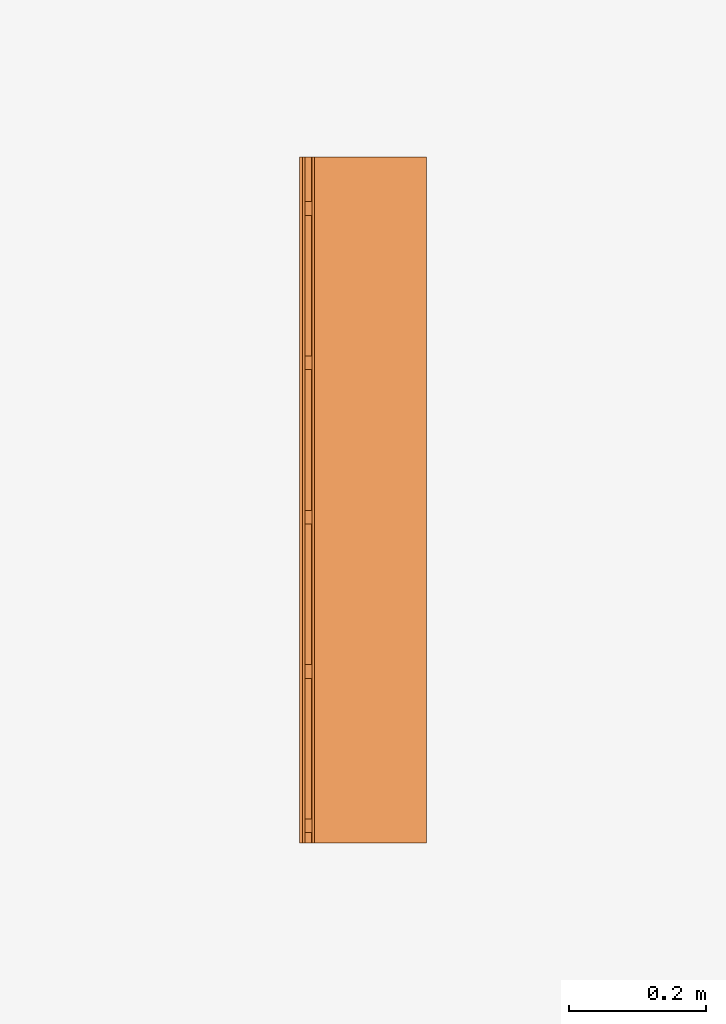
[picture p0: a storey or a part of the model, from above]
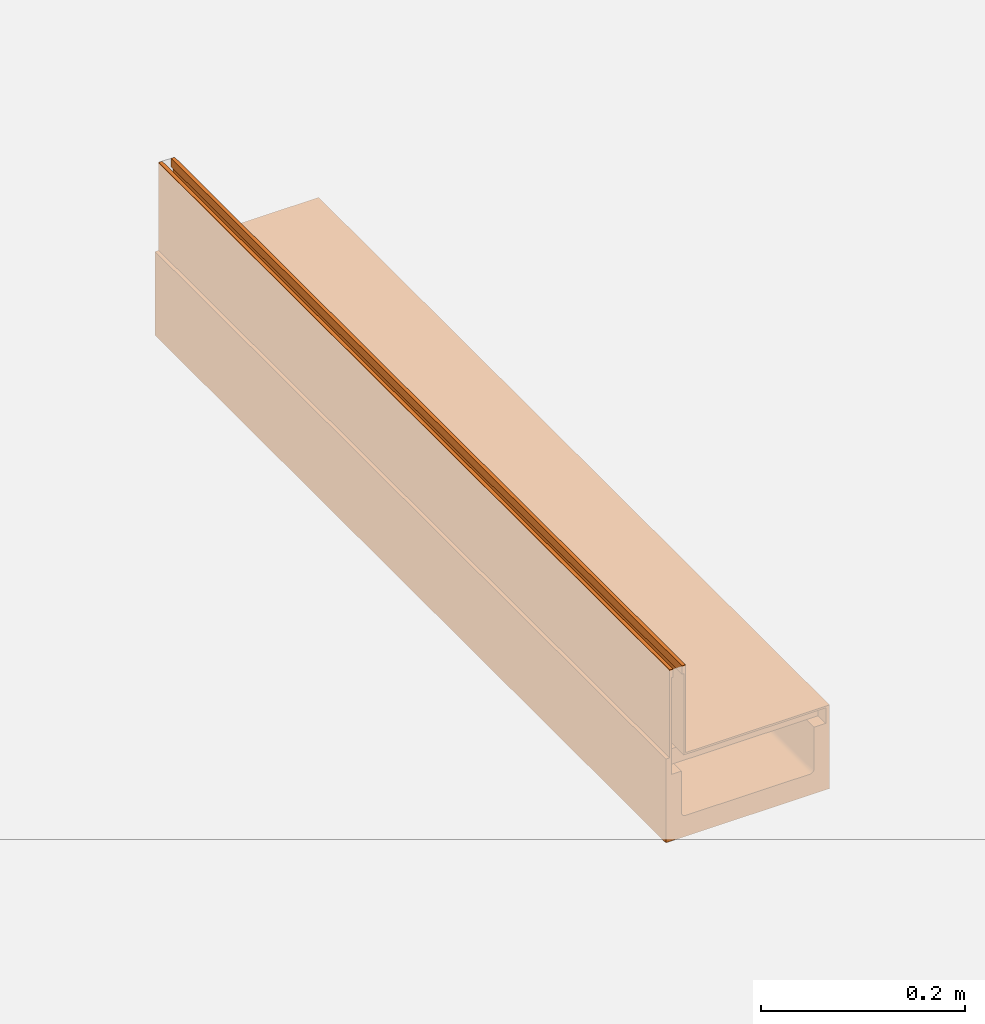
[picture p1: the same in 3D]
Properties of the parts of a building model (IFC2X3)

# File
Description: ViewDefinition [CoordinationView]
File name: 24157 - No 0100V - Shallow Depth Channel - 1000mm LG - Invert Depth 75mm.ifc
Time: 2013-10-30T13:31:54
Written by: Autodesk Revit 2013
Made in: 20120221_2030(x64)

# IfcProject, Project Number
LongName: Project Name; Phase: Project Status

# IfcSite, Default
RefLatitude: 42, 21, 30, 344238; RefLongitude: -71, -3, -35, -194702; RefElevation: 0 mm

# IfcBuilding
Pset_BuildingCommon - NumberOfStoreys: 1
Other - Project Issue Date: Issue Date; Project Address: ## Street City, State Zip; Client Name: Owner; Project Status: Project Status; Project Name: Project Name; Project Number: Project Number

# IfcBuildingStorey, Level 1
LongName: Level 1; Elevation: 0 mm
Constraints - Elevation Base: 0; Elevation: 0 mm
Graphics - Symbol: M_Level Head - Circle: M_Level Head - Circle; Symbol at End 2 Default: yes; Line Pattern: Center; Color: 0; Symbol at End 1 Default: no; Line Weight: 1
Dimensions - Computation Height: 0 mm
Identity Data - Name: Level 1; Building Story: yes; Structural: no

# IfcBuildingElementProxy: 24157 - No 0100V - Shallow Depth Channel - 1000mm LG - Invert Depth 75mm, Civil-Drainage-Channel-ACO-MultiDrain-M150DS-Brickslot-Channel-System:24157 - No 0100V - Shallow Depth Channel - 1000mm LG - Invert Depth 75mm:24157 - No 0100V - Shallow Depth Channel - 1000mm LG - Invert Depth 75mm:196059
In: Level 1
Material: Stainless Steel (F), Plastic, Opaque Black, Vienite® Synthetic Resin Concrete
Other - Revision: 1; CreatedBy: www.aco.co.uk
Dimensions - FloorCut_Length: -1000 mm; Brickslot Void Length: -1000 mm; Length: 1000 mm; EndCap Position: 1000 mm; Brickslot Access Unit Void Depth: 6000 mm; Brickslot Grating Void Depth: 0 mm; Volume: 7499066 mm3; Custom_Void_Length: 0 mm; Brickslot Access Unit Void Bottom Depth: 5895 mm; FloorCut_Depth: 100 mm; EndCap_Height: -100 mm; Length Drain: -1000 mm; Floor cut gap depth for access unit: 105 mm; FloorCut_Width: 185 mm; Depth: 310 mm; FloorCut_HorPosition: 92.5 mm; InvDepth: 210 mm; GratingLength: 0 mm; Floor Cut Gap: 105 mm
Constraints - Moves With Nearby Elements: no; Level: Level: Level 1
Construction - 23186_Load Class C250 & D400_Brickslot Grating_Stainless Steel_500mm Long: no; 24187_Load Class C250 & D400_Brickslot_Access Unit_Stainless Steel_500mm Long: no; 23185_Load Class C250 & D400_Brickslot Grating_Stainless Steel_1000mm Long: yes; 23159_Universal Endcap (Female End): no; 23159_Universal Endcap (Male End): no; 24157_Shallow Depth Channel with seal: yes; Constant Depth Channel_1000: no; 24156_Shallow Depth Channel: no; Constant Depth Channel_500: no; 24158_Sump Unit: no
Phasing - Phase Created: New Construction
Pset_BuildingElementProxyCommon - Reference: 24157 - No 0100V - Shallow Depth Channel - 1000mm LG - Invert Depth 75mm
General - SerialNumber: 0; TagNumber: 0
Identity Data - Manufacturer: ACO Technologies plc - ACO Water Management Division; Watermark 1: This file is the property of ACO Technologies PLC; Installation guidelines: http://www.aco.co.uk/download.php?id=173; Watermarked With: BIM Manager Premium Suite; Product Page URL: http://www.aco.co.uk/product_detail.php?id=58; OmniClass Title: Rainwater Removal; Model Description: Channel drainage system; Watermark 2: This file is water marked and users are prohibited to reproduce, adapt, distribute this information; Telephone: +44 (0)1462 816666; URL: www.aco.co.uk; Product Code: 24157; Address: ACO Business Park, Hitchin Road, Shefford, Bedfordshire, United Kingdom SG17 5TE; Model: ACO MultiDrain MDS Brickslot - M150DS; OmniClass Number: 23.70.50.24; Assembly Description: Rain Water Drainage; Price: POA - contact ACO; Maintenance guidelines: http://www.aco.co.uk/download.php?id=173; e-mail Sales: customersupport@aco.co.uk; Assembly Code: D2040; Fax: +44 (0)1462 815895; Watermarked By: www.aco.co.uk; Cost: 0; e-mail Technical: technical@aco.co.uk; Product brochure: http://www.aco.co.uk/download.php?id=173; Type Comments: ACO MultiDrain M150DS 0100V Shallow Constant Depth Channel 1000mm Long
Green Building Properties - Channel Recyclable: Fully recyclable; Edge Rail Recyclable: Fully recyclable; Channel Recycled Material Content: 20% minimum; Edge Rail Recycled Material Content: Between 40% - 90%
Model Properties - Brickslot Access Unit Product code 23187: Load Class C250/D400 - Brickslot Access Unit Stainless Steel - 500mm long x 105mm high - 10mm Slot - Intake area 10000mm²/m - 6.4kg; Brickslot Grating Product code 23186: Load Class C250/D400 -Brickslot Stainless Steel - 500mm long x 105mm high - 10mm Slot - Intake area 10000mm²/m - 3.8kg; Brickslot Grating Product code 23185: Load Class C250/D400 - Brickslot Stainless Steel - 1000mm long x 105mm high - 10mm Slot - Intake area 10000mm²/m - 7.6kg; End Cap Product code 23219: No. 306 Universal End Cap - 185mm wide x 310mm long - Spigot Ø110mm x 50mm long - Silver - Co-Polymer Polypropylene - 0.3kg
Data - Channel C.S.A: 0.008m²; Pre-formed Outlet Ø: N/A; Concrete Surround Volume - Load Class D 400 - Concrete Pavement: 0.16m³/m; Load Class: A 15 - D 400; Product Weight: 15.9 Kg; Concrete Surround Volume - Load Class A 15 - Concrete Pavement: 0.06m³/m; Invert Depth: 75mm; Product Standard: BS EN 1433:2002, CE marked; Installation - Concrete Grade: Refer to brochure; ACO Hydraulic Design Software: http://www.acodesign.co.uk; Hydraulic Performance: http://www.aco.co.uk/download.php?id=173; Product Dimensions: 1000mm x 185mm x 100mm (LxWxH); Concrete Surround Volume - Load Class B 125 - C 250 - Concrete Pavement: 0.10m³/m
Materials and Finishes - Channel Material: Vienite® Synthetic Resin Concrete; Edge Rail Colour: Self; Edge Rail Material: Stainless Steel Grade 304; Channel Colour: Brown

# IfcOpeningElement: Opening, Civil-Drainage-Channel-ACO-MultiDrain-M150DS-Brickslot-Channel-System:24157 - No 0100V - Shallow Depth Channel - 1000mm LG - Invert Depth 75mm:24157 - No 0100V - Shallow Depth Channel - 1000mm LG - Invert Depth 75mm:196059:1
In: Level 1
Other - Revision: 1; CreatedBy: www.aco.co.uk
Dimensions - FloorCut_Length: -1000 mm; Brickslot Void Length: -1000 mm; Length: 1000 mm; EndCap Position: 1000 mm; Brickslot Access Unit Void Depth: 6000 mm; Brickslot Grating Void Depth: 0 mm; Volume: 7499066 mm3; Custom_Void_Length: 0 mm; Brickslot Access Unit Void Bottom Depth: 5895 mm; FloorCut_Depth: 100 mm; EndCap_Height: -100 mm; Length Drain: -1000 mm; Floor cut gap depth for access unit: 105 mm; FloorCut_Width: 185 mm; Depth: 310 mm; FloorCut_HorPosition: 92.5 mm; InvDepth: 210 mm; GratingLength: 0 mm; Floor Cut Gap: 105 mm
Constraints - Moves With Nearby Elements: no; Level: Level: Level 1
Construction - 23186_Load Class C250 & D400_Brickslot Grating_Stainless Steel_500mm Long: no; 24187_Load Class C250 & D400_Brickslot_Access Unit_Stainless Steel_500mm Long: no; 23185_Load Class C250 & D400_Brickslot Grating_Stainless Steel_1000mm Long: yes; 23159_Universal Endcap (Female End): no; 23159_Universal Endcap (Male End): no; 24157_Shallow Depth Channel with seal: yes; Constant Depth Channel_1000: no; 24156_Shallow Depth Channel: no; Constant Depth Channel_500: no; 24158_Sump Unit: no
Phasing - Phase Created: New Construction
General - SerialNumber: 0; TagNumber: 0
Identity Data - Manufacturer: ACO Technologies plc - ACO Water Management Division; Watermark 1: This file is the property of ACO Technologies PLC; Installation guidelines: http://www.aco.co.uk/download.php?id=173; Watermarked With: BIM Manager Premium Suite; Product Page URL: http://www.aco.co.uk/product_detail.php?id=58; OmniClass Title: Rainwater Removal; Model Description: Channel drainage system; Watermark 2: This file is water marked and users are prohibited to reproduce, adapt, distribute this information; Telephone: +44 (0)1462 816666; URL: www.aco.co.uk; Product Code: 24157; Address: ACO Business Park, Hitchin Road, Shefford, Bedfordshire, United Kingdom SG17 5TE; Model: ACO MultiDrain MDS Brickslot - M150DS; OmniClass Number: 23.70.50.24; Assembly Description: Rain Water Drainage; Price: POA - contact ACO; Maintenance guidelines: http://www.aco.co.uk/download.php?id=173; e-mail Sales: customersupport@aco.co.uk; Assembly Code: D2040; Fax: +44 (0)1462 815895; Watermarked By: www.aco.co.uk; Cost: 0; e-mail Technical: technical@aco.co.uk; Product brochure: http://www.aco.co.uk/download.php?id=173; Type Comments: ACO MultiDrain M150DS 0100V Shallow Constant Depth Channel 1000mm Long
Green Building Properties - Channel Recyclable: Fully recyclable; Edge Rail Recyclable: Fully recyclable; Channel Recycled Material Content: 20% minimum; Edge Rail Recycled Material Content: Between 40% - 90%
Model Properties - Brickslot Access Unit Product code 23187: Load Class C250/D400 - Brickslot Access Unit Stainless Steel - 500mm long x 105mm high - 10mm Slot - Intake area 10000mm²/m - 6.4kg; Brickslot Grating Product code 23186: Load Class C250/D400 -Brickslot Stainless Steel - 500mm long x 105mm high - 10mm Slot - Intake area 10000mm²/m - 3.8kg; Brickslot Grating Product code 23185: Load Class C250/D400 - Brickslot Stainless Steel - 1000mm long x 105mm high - 10mm Slot - Intake area 10000mm²/m - 7.6kg; End Cap Product code 23219: No. 306 Universal End Cap - 185mm wide x 310mm long - Spigot Ø110mm x 50mm long - Silver - Co-Polymer Polypropylene - 0.3kg
Data - Channel C.S.A: 0.008m²; Pre-formed Outlet Ø: N/A; Concrete Surround Volume - Load Class D 400 - Concrete Pavement: 0.16m³/m; Load Class: A 15 - D 400; Product Weight: 15.9 Kg; Concrete Surround Volume - Load Class A 15 - Concrete Pavement: 0.06m³/m; Invert Depth: 75mm; Product Standard: BS EN 1433:2002, CE marked; Installation - Concrete Grade: Refer to brochure; ACO Hydraulic Design Software: http://www.acodesign.co.uk; Hydraulic Performance: http://www.aco.co.uk/download.php?id=173; Product Dimensions: 1000mm x 185mm x 100mm (LxWxH); Concrete Surround Volume - Load Class B 125 - C 250 - Concrete Pavement: 0.10m³/m
Materials and Finishes - Channel Material: Vienite® Synthetic Resin Concrete; Edge Rail Colour: Self; Edge Rail Material: Stainless Steel Grade 304; Channel Colour: Brown

# IfcOpeningElement: Recess (2)
In: Level 1
Constraints - Level: Level: Level 1; Room Bounding: yes; Height Offset From Level: 0 mm; Related to Mass: no
Dimensions - Volume: 9979610000 mm3; Area: 25000000 mm2; Thickness: 400 mm; Perimeter: 20000 mm
Structural - Structural: no; Enable Analytical Model: no
Phasing - Phase Created: New Construction
Analytical Properties - Roughness: 1; Thermal mass: 543920; Absorptance: 0.1; Thermal Resistance (R): 0.477897; Heat Transfer Coefficient (U): 2.0925
Materials and Finishes - Structural Material: Earth
Construction - Default Thickness: 400 mm; Function: 0
Graphics - Coarse Scale Fill Color: 0

# IfcSlab: Floor:Generic Floor - 400mm, Floor:Generic Floor - 400mm:193825
In: Level 1
PredefinedType: FLOOR; Material: Earth 400 mm
Constraints - Level: Level: Level 1; Room Bounding: yes; Height Offset From Level: 0 mm; Related to Mass: no
Dimensions - Volume: 9979610000 mm3; Area: 25000000 mm2; Thickness: 400 mm; Perimeter: 20000 mm
Structural - Structural: no; Enable Analytical Model: no
Phasing - Phase Created: New Construction
Pset_SlabCommon - Reference: Generic Floor - 400mm; IsExternal: no; LoadBearing: yes
Analytical Properties - Roughness: 1; Thermal mass: 543920; Absorptance: 0.1; Thermal Resistance (R): 0.477897; Heat Transfer Coefficient (U): 2.0925
Materials and Finishes - Structural Material: Earth
Construction - Default Thickness: 400 mm; Function: 0
Graphics - Coarse Scale Fill Color: 0
